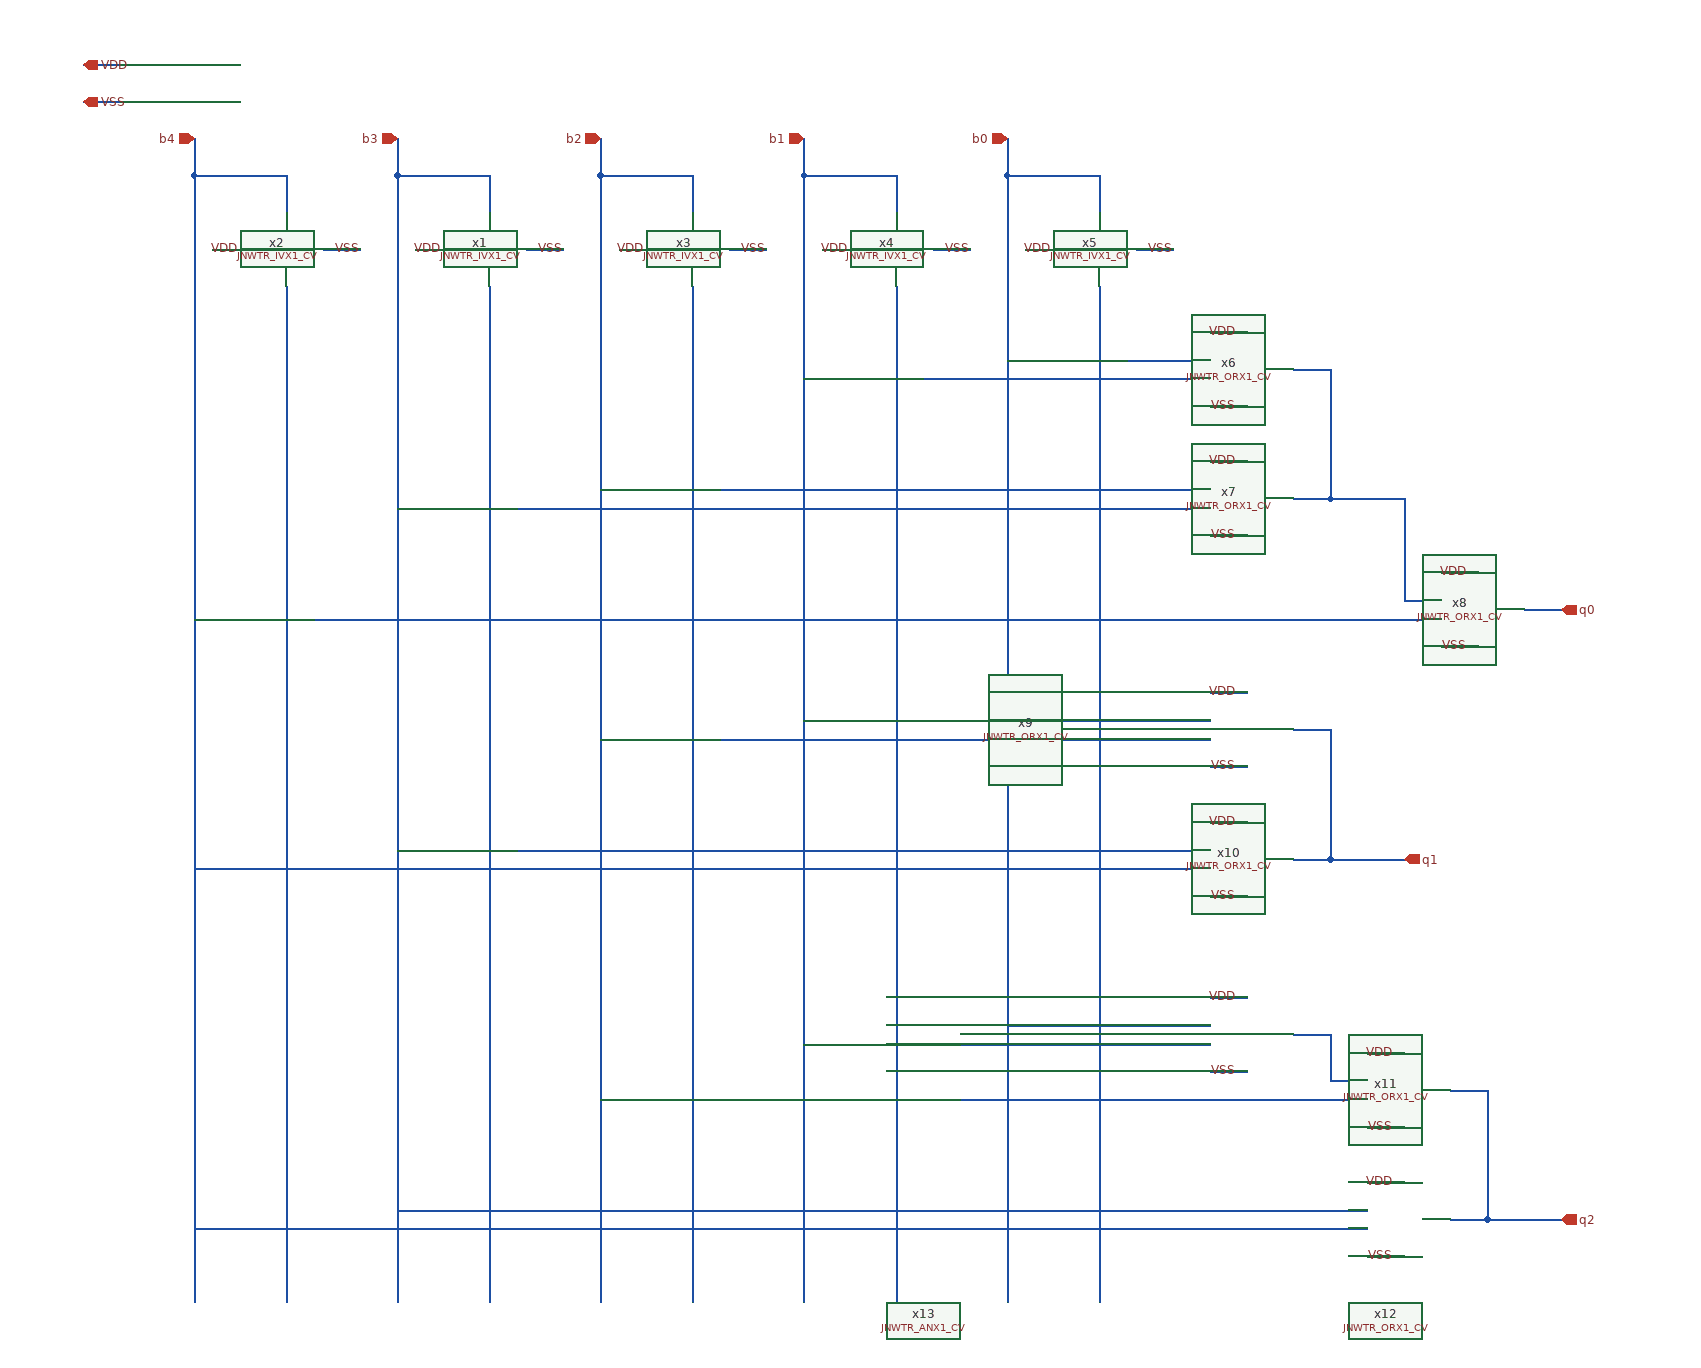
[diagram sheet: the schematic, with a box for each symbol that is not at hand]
v {xschem version=3.4.6 file_version=1.2}
G {}
K {}
V {}
S {}
E {}
N 340 180 340 220 {lab=b4}
N 240 180 340 180 {lab=b4}
N 240 180 240 860 {lab=b4}
N 340 300 340 860 {lab=#net1}
N 240 140 240 180 {lab=b4}
N 260 260 300 260 {lab=VDD}
N 380 260 420 260 {lab=VSS}
N 560 180 560 220 {lab=b3}
N 460 180 560 180 {lab=b3}
N 460 180 460 860 {lab=b3}
N 560 300 560 860 {lab=#net2}
N 460 140 460 180 {lab=b3}
N 480 260 520 260 {lab=VDD}
N 600 260 640 260 {lab=VSS}
N 780 180 780 220 {lab=b2}
N 680 180 780 180 {lab=b2}
N 680 180 680 860 {lab=b2}
N 780 300 780 860 {lab=#net3}
N 680 140 680 180 {lab=b2}
N 700 260 740 260 {lab=VDD}
N 820 260 860 260 {lab=VSS}
N 1000 180 1000 220 {lab=b1}
N 900 180 1000 180 {lab=b1}
N 900 180 900 860 {lab=b1}
N 1000 300 1000 860 {lab=#net4}
N 900 140 900 180 {lab=b1}
N 920 260 960 260 {lab=VDD}
N 1040 260 1080 260 {lab=VSS}
N 1220 180 1220 220 {lab=b0}
N 1120 180 1220 180 {lab=b0}
N 1120 180 1120 860 {lab=b0}
N 1220 300 1220 860 {lab=#net5}
N 1120 140 1120 180 {lab=b0}
N 1140 260 1180 260 {lab=VDD}
N 1260 260 1300 260 {lab=VSS}
N 1120 380 1300 380 {lab=b0}
N 900 400 1300 400 {lab=b1}
N 680 520 1300 520 {lab=b2}
N 460 540 1300 540 {lab=b3}
N 240 660 1300 660 {lab=b4}
N 1300 380 1340 380 {lab=b0}
N 1300 400 1340 400 {lab=b1}
N 1340 350 1380 350 {lab=VDD}
N 1340 430 1380 430 {lab=VSS}
N 1430 390 1470 390 {lab=#net6}
N 1340 490 1380 490 {lab=VDD}
N 1340 570 1380 570 {lab=VSS}
N 1430 530 1470 530 {lab=#net6}
N 1300 520 1340 520 {lab=b2}
N 1300 540 1340 540 {lab=b3}
N 1470 460 1470 530 {lab=#net6}
N 1470 530 1550 530 {lab=#net6}
N 1470 390 1470 440 {lab=#net6}
N 1300 660 1550 660 {lab=b4}
N 1550 530 1550 550 {lab=#net6}
N 1470 440 1470 460 {lab=#net6}
N 1590 610 1630 610 {lab=VDD}
N 1590 690 1630 690 {lab=VSS}
N 1680 650 1720 650 {lab=q0}
N 1550 640 1590 640 {lab=#net6}
N 1550 660 1590 660 {lab=b4}
N 1550 550 1550 640 {lab=#net6}
N 680 790 1340 790 {lab=b2}
N 900 770 1340 770 {lab=b1}
N 1340 740 1380 740 {lab=VDD}
N 1340 820 1380 820 {lab=VSS}
N 1430 780 1470 780 {lab=q1}
N 1340 880 1380 880 {lab=VDD}
N 1340 960 1380 960 {lab=VSS}
N 1430 920 1470 920 {lab=q1}
N 460 910 1340 910 {lab=b3}
N 240 930 1340 930 {lab=b4}
N 1470 850 1470 920 {lab=q1}
N 1470 920 1550 920 {lab=q1}
N 1470 780 1470 830 {lab=q1}
N 1470 830 1470 850 {lab=q1}
N 240 860 240 1400 {lab=b4}
N 340 860 340 1400 {lab=#net1}
N 460 860 460 1400 {lab=b3}
N 560 860 560 1400 {lab=#net2}
N 680 860 680 1400 {lab=b2}
N 780 860 780 1400 {lab=#net3}
N 900 860 900 1400 {lab=b1}
N 1000 860 1000 1400 {lab=#net4}
N 1120 860 1120 1400 {lab=b0}
N 1220 860 1220 1400 {lab=#net5}
N 460 1300 1510 1300 {lab=b3}
N 680 1180 1510 1180 {lab=b2}
N 1510 1130 1550 1130 {lab=VDD}
N 1510 1210 1550 1210 {lab=VSS}
N 1600 1170 1640 1170 {lab=q0}
N 1510 1270 1550 1270 {lab=VDD}
N 1510 1350 1550 1350 {lab=VSS}
N 1600 1310 1640 1310 {lab=q0}
N 240 1320 1510 1320 {lab=b4}
N 1470 1160 1510 1160 {lab=#net7}
N 1640 1240 1640 1310 {lab=q0}
N 1640 1310 1720 1310 {lab=q0}
N 1640 1170 1640 1220 {lab=q0}
N 1640 1220 1640 1240 {lab=q0}
N 1430 1110 1470 1110 {lab=#net7}
N 1470 1110 1470 1160 {lab=#net7}
N 1120 1100 1340 1100 {lab=b0}
N 900 1120 1340 1120 {lab=b1}
N 1340 1070 1380 1070 {lab=VDD}
N 1340 1150 1380 1150 {lab=VSS}
N 120 60 160 60 {lab=VDD}
N 120 100 160 100 {lab=VSS}
C {JNW_TR_SKY130A/JNWTR_IVX1_CV.sym} 340 220 3 1 {name=x2 }
C {JNW_TR_SKY130A/JNWTR_IVX1_CV.sym} 560 220 3 1 {name=x1 }
C {JNW_TR_SKY130A/JNWTR_IVX1_CV.sym} 780 220 3 1 {name=x3 }
C {JNW_TR_SKY130A/JNWTR_IVX1_CV.sym} 1000 220 3 1 {name=x4 }
C {JNW_TR_SKY130A/JNWTR_IVX1_CV.sym} 1220 220 3 1 {name=x5 }
C {devices/ipin.sym} 1120 140 1 0 {name=p2 lab=b0}
C {devices/ipin.sym} 900 140 1 0 {name=p3 lab=b1}
C {devices/ipin.sym} 680 140 1 0 {name=p4 lab=b2}
C {devices/ipin.sym} 460 140 1 0 {name=p5 lab=b3}
C {devices/ipin.sym} 240 140 1 0 {name=p6 lab=b4}
C {devices/ipin.sym} 120 60 2 1 {name=p9 lab=VDD}
C {devices/ipin.sym} 120 100 2 1 {name=p10 lab=VSS}
C {devices/lab_wire.sym} 290 260 0 0 {name=p11 sig_type=std_logic lab=VDD}
C {devices/lab_wire.sym} 390 260 0 1 {name=p12 sig_type=std_logic lab=VSS}
C {devices/lab_wire.sym} 610 260 0 1 {name=p13 sig_type=std_logic lab=VSS}
C {devices/lab_wire.sym} 510 260 0 0 {name=p14 sig_type=std_logic lab=VDD}
C {devices/lab_wire.sym} 730 260 0 0 {name=p15 sig_type=std_logic lab=VDD}
C {devices/lab_wire.sym} 950 260 0 0 {name=p16 sig_type=std_logic lab=VDD}
C {devices/lab_wire.sym} 1170 260 0 0 {name=p17 sig_type=std_logic lab=VDD}
C {devices/lab_wire.sym} 830 260 0 1 {name=p18 sig_type=std_logic lab=VSS}
C {devices/lab_wire.sym} 1050 260 0 1 {name=p19 sig_type=std_logic lab=VSS}
C {devices/lab_wire.sym} 1270 260 0 1 {name=p20 sig_type=std_logic lab=VSS}
C {JNW_TR_SKY130A/JNWTR_ORX1_CV.sym} 1340 400 0 0 {name=x6 }
C {devices/lab_wire.sym} 1370 350 0 0 {name=p25 sig_type=std_logic lab=VDD}
C {devices/lab_wire.sym} 1370 430 2 1 {name=p26 sig_type=std_logic lab=VSS}
C {JNW_TR_SKY130A/JNWTR_ORX1_CV.sym} 1340 540 0 0 {name=x7 }
C {devices/lab_wire.sym} 1370 490 0 0 {name=p27 sig_type=std_logic lab=VDD}
C {devices/lab_wire.sym} 1370 570 2 1 {name=p28 sig_type=std_logic lab=VSS}
C {devices/opin.sym} 1720 650 0 0 {name=p29 lab=q0}
C {JNW_TR_SKY130A/JNWTR_ORX1_CV.sym} 1590 660 0 0 {name=x8 }
C {devices/lab_wire.sym} 1620 610 0 0 {name=p30 sig_type=std_logic lab=VDD}
C {devices/lab_wire.sym} 1620 690 2 1 {name=p31 sig_type=std_logic lab=VSS}
C {JNW_TR_SKY130A/JNWTR_ORX1_CV.sym} 1340 790 0 0 {name=x9 }
C {devices/lab_wire.sym} 1370 740 0 0 {name=p1 sig_type=std_logic lab=VDD}
C {devices/lab_wire.sym} 1370 820 2 1 {name=p7 sig_type=std_logic lab=VSS}
C {JNW_TR_SKY130A/JNWTR_ORX1_CV.sym} 1340 930 0 0 {name=x10 }
C {devices/lab_wire.sym} 1370 880 0 0 {name=p8 sig_type=std_logic lab=VDD}
C {devices/lab_wire.sym} 1370 960 2 1 {name=p21 sig_type=std_logic lab=VSS}
C {JNW_TR_SKY130A/JNWTR_ORX1_CV.sym} 1510 1180 0 0 {name=x11 }
C {devices/lab_wire.sym} 1540 1130 0 0 {name=p22 sig_type=std_logic lab=VDD}
C {devices/lab_wire.sym} 1540 1210 2 1 {name=p23 sig_type=std_logic lab=VSS}
C {JNW_TR_SKY130A/JNWTR_ORX1_CV.sym} 1510 1320 0 0 {name=x12 }
C {devices/lab_wire.sym} 1540 1270 0 0 {name=p24 sig_type=std_logic lab=VDD}
C {devices/lab_wire.sym} 1540 1350 2 1 {name=p32 sig_type=std_logic lab=VSS}
C {JNW_TR_SKY130A/JNWTR_ANX1_CV.sym} 1340 1120 0 0 {name=x13 }
C {devices/lab_wire.sym} 1370 1070 0 0 {name=p33 sig_type=std_logic lab=VDD}
C {devices/lab_wire.sym} 1370 1150 2 1 {name=p34 sig_type=std_logic lab=VSS}
C {devices/opin.sym} 1550 920 0 0 {name=p35 lab=q1}
C {devices/opin.sym} 1720 1310 0 0 {name=p36 lab=q2}
